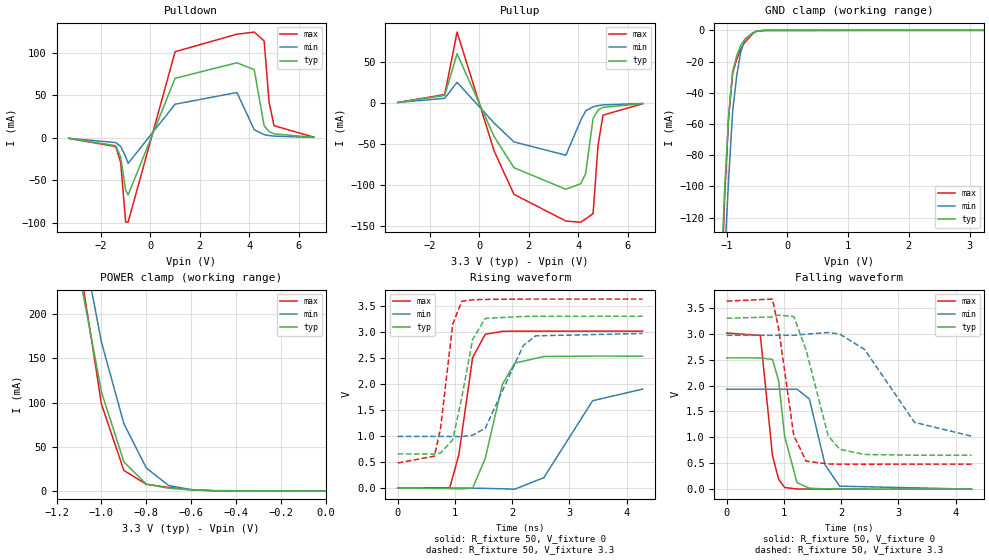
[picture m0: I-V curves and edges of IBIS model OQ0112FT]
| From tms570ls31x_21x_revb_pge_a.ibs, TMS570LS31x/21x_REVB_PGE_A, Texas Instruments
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|   Model Cell OQ0112FT
|OQ0112FT
[Model]   OQ0112FT
Model_type   3-state
Polarity   Non-Inverting
Enable   Active-Low
Cref =  15.0001pF
Rref =  101.0000M
Vref =  0V
Vmeas =  1.65
C_comp   1.2p   1.2p   1.2p
[Temperature Range]   25   155   -40
[Voltage Range]   3.3   2.97   3.63
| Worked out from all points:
|   slope of the pulldown table from 0 to 0.495 V, typ, clamps not added: 11.9 ohm
|   slope of the pullup table from 0 to 0.495 V, typ, clamps not added: 14.3 ohm
|   GND clamp passes 1 mA (typ) near -0.53 V on its own axis
|   POWER clamp passes 1 mA (typ) near -0.59 V on its own axis
|   rising waveform, R_fixture 50, V_fixture 0: 20-80 % time 331ps typ, 609ps min, 230ps max; typ from 0 V to 2.53 V
|   rising waveform, R_fixture 50, V_fixture 3.3: 20-80 % time 260ps typ, 440ps min, 196ps max; typ from 0.657 V to 3.3 V
|   falling waveform, R_fixture 50, V_fixture 0: 20-80 % time 175ps typ, 253ps min, 146ps max; typ from 2.53 V to 0 V
|   falling waveform, R_fixture 50, V_fixture 3.3: 20-80 % time 357ps typ, 692ps min, 240ps max; typ from 3.3 V to 0.656 V
[POWER_clamp]
|   voltage   I(typ)   I(min)   I(max)
-3.3V     4.053A     4.629A     4.886A
-1.1V     248.2mA    300.9mA    262.6mA
-1.067V   202.9mA    256.8mA    207.9mA
-1.033V   157.5mA    212.7mA    153.1mA
-1V       112.1mA    168.5mA    98.27mA
-900mV    32.87mA    76.19mA    23.22mA
-800mV    7.703mA    25.93mA    7.474mA
-700mV    3.032mA    6.035mA    3.99mA
-600mV    1.087mA    1.527mA    1.425mA
-500mV    187uA      368.8uA    203.4uA
0V        413.3pA    6.127nA    384.2pA
[Pulldown]
|   voltage   I(typ)   I(min)   I(max)
-3.3V     -592.9uA   -522.5uA   -579.7uA
-1.4V     -9.185mA   -5.564mA   -10.34mA
-1.2V     -22.55mA   -10.08mA   -29.08mA
-1V       -61.67mA   -22.23mA   -99.18mA
-900mV    -67.23mA   -30.1mA    -99.38mA
1V        70.16mA    39.61mA    101.5mA
3.5V      88.44mA    53.41mA    122.1mA
4.2V      80.27mA    9.542mA    124.6mA
4.6V      14.18mA    3.749mA    114.2mA
4.8V      7.417mA    2.695mA    42.04mA
5V        4.686mA    2.03mA     14.29mA
6.6V      680.4uA    493.7uA    947.4uA
[Pullup]
|   voltage   I(typ)   I(min)   I(max)
-3.3V     671.9uA    618.2uA    613uA
-1.4V     9.171mA    5.686mA    10.35mA
-900mV    59.98mA    25.21mA    86.36mA
600mV     -40.93mA   -24.46mA   -58.45mA
1.4V      -78.76mA   -47.34mA   -111.2mA
3.5V      -105mA     -63.56mA   -143.7mA
4.1V      -98.18mA   -21.1mA    -145.1mA
4.3V      -85.93mA   -9.608mA   -141.1mA
4.6V      -18.69mA   -4.516mA   -134.7mA
4.8V      -8.688mA   -3.128mA   -51.39mA
5V        -5.24mA    -2.297mA   -14.79mA
6.6V      -711.6uA   -541.3uA   -920.1uA
[GND_clamp]
|   voltage   I(typ)   I(min)   I(max)
-3.3V     -3.244A    -2.872A    -4.921A
-1.1V     -166.2mA   -204.6mA   -184.6mA
-1.033V   -102.2mA   -146.3mA   -108.2mA
-966.7mV  -55.54mA   -95.39mA   -55.76mA
-900mV    -26.29mA   -51.8mA    -27.26mA
-833.3mV  -16.36mA   -29.13mA   -18.56mA
-766.7mV  -9.496mA   -13.82mA   -12.04mA
-700mV    -5.684mA   -5.889mA   -7.701mA
-566.7mV  -1.566mA   -1.626mA   -2.053mA
-500mV    -402.1uA   -593.5uA   -459.6uA
-366.7mV  -18.7uA    -59.18uA   -17.4uA
3.233V    394.5pA    4.088uA    294.2pA
[Ramp]
| variable   typ   min   max
dV/dt_f   1.638484/0.3685395n   1.223459/0.7247682n   1.952815/0.2468409n
dV/dt_r   1.537785/0.3309066n   1.172668/0.6304095n   1.826916/0.2301081n
R_load = 50
[Rising Waveform]
R_fixture = 50
V_fixture = 0
V_fixture_min = 0
V_fixture_max = 0
|   time   V(typ)   V(min)   V(max)
0s        -1.087uV   -587.8nV   40.54nV
908ps     -8.078mV   170.5uV    4.494mV
1.068ns   -15.3mV    67.94uV    643.9mV
1.308ns   -1.475mV   -2.053mV   2.506V
1.528ns   570.7mV    -5.374mV   2.954V
1.828ns   1.991V     -13.04mV   3.01V
2.044ns   2.4V       -20.3mV    3.015V
2.552ns   2.527V     200.1mV    3.015V
3.404ns   2.535V     1.678V     3.014V
4.276ns   2.534V     1.901V     3.014V
[Rising Waveform]
R_fixture = 50
V_fixture = 3.3
V_fixture_min = 2.97
V_fixture_max = 3.63
|   time   V(typ)   V(min)   V(max)
0s        656.6mV    993.3mV    482.5mV
640ps     655mV      993.3mV    613.8mV
748ps     673.8mV    993.1mV    1.149V
960ps     925.4mV    990.1mV    3.148V
1.12ns    1.746V     988.4mV    3.589V
1.308ns   2.854V     1.017V     3.616V
1.528ns   3.258V     1.148V     3.623V
2.192ns   3.296V     2.736V     3.63V
2.408ns   3.299V     2.924V     3.63V
4.276ns   3.3V       2.969V     3.63V
[Falling Waveform]
R_fixture = 50
V_fixture = 0
V_fixture_min = 0
V_fixture_max = 0
|   time   V(typ)   V(min)   V(max)
0s        2.534V     1.93V      3.014V
588ps     2.533V     1.93V      2.969V
800ps     2.505V     1.93V      645.3mV
908ps     2.087V     1.93V      190.1mV
1.012ns   1.02V      1.93V      32mV
1.228ns   126.2mV    1.93V      3.766mV
1.444ns   17.64mV    1.741V     1.71mV
1.72ns    4.98mV     467.7mV    224.3uV
1.972ns   2.504mV    58.03mV    -74.45uV
4.276ns   20.32uV    623.2uV    10.27uV
[Falling Waveform]
R_fixture = 50
V_fixture = 3.3
V_fixture_min = 2.97
V_fixture_max = 3.63
|   time   V(typ)   V(min)   V(max)
0s        3.3V       2.97V      3.63V
800ps     3.324V     2.97V      3.67V
908ps     3.359V     2.97V      3.094V
1.172ns   3.333V     2.97V      1.034V
1.388ns   2.682V     2.992V     540.6mV
1.772ns   1.032V     3.024V     486.4mV
1.972ns   770.8mV    2.995V     482.7mV
2.408ns   670mV      2.698V     481.8mV
3.28ns    655.4mV    1.29V      482.3mV
4.276ns   655.9mV    1.023V     482.4mV
